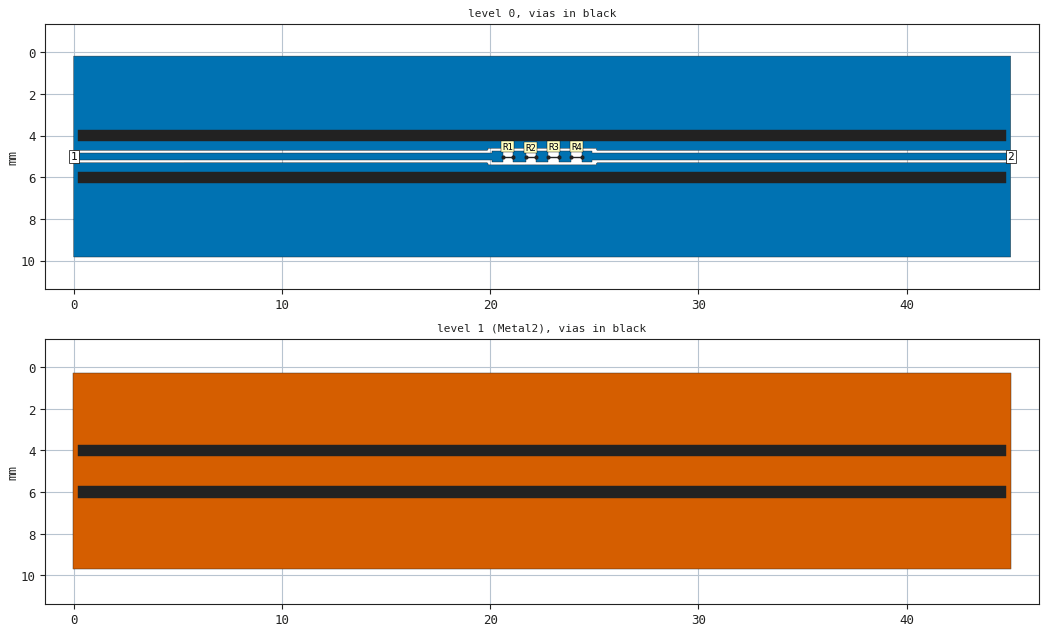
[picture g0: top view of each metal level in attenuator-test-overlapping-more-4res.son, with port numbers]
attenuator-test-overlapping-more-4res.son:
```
FTYP SONPROJ 17 ! Sonnet Project File
VER 17.52.2
HEADER
LIC antikernel2.2.49648 90e2ba8817c0 havequick azonenberg
DAT 08/30/2020 02:43:10
BUILT_BY_CREATED xgeom 16.56 07/03/2018 15:05:41
BUILT_BY_SAVED sonnet 17.52.2
MDATE 08/30/2020 02:41:37
HDATE 08/30/2020 02:41:37
END HEADER
DIM
ANG DEG
CAP PF
CON /OH
FREQ GHZ
IND NH
LNG MM
RES OH
END DIM
CONTROL
VARSWP
OPTIONS  -dj
SPEED 1
CACHE_ABS 1
Q_ACC N
END CONTROL
GEO
TMET "Free Space" 0 FREESPACE 376.7303136 0 0 0
BMET "Free Space" 0 FREESPACE 376.7303136 0 0 0
MET "Silver" 1 TMM 61700000 0.5 0.035 2
BRI "Alumina (96%)" 0 9.4 0.0004 0 
BRI "Alumina (99.5%)" 0 9.9 0.0001 0 
BRI "Aluminum Nitride" 0 8.6 0.0003 0 
BRI "Arlon 25FR" 0 3.58 0.0035 0 
BRI "Arlon 25N" 0 3.38 0.0025 0 
BRI "Arlon AD5" 0 5.1 0.003 0 
BRI "Arlon AD10" 0 10.2 0.005 0 
BRI "Arlon AD250" 0 2.5 0.0018 0 
BRI "Arlon AD255A" 0 2.55 0.0015 0 
BRI "Arlon AD260A" 0 2.6 0.0018 0 
BRI "Arlon AD270" 0 2.7 0.0023 0 
BRI "Arlon AD300A" 0 3 0.002 0 
BRI "Arlon AD320A" 0 3.2 0.0032 0 
BRI "Arlon AD350A" 0 3.5 0.003 0 
BRI "Arlon AD410" 0 4.1 0.003 0 
BRI "Arlon AD430" 0 4.3 0.003 0 
BRI "Arlon AD450" 0 4.5 0.0035 0 
BRI "Arlon AD600" 0 6.15 0.003 0 
BRI "Arlon AD1000" 0 10.2 0.0023 0 
BRI "Arlon AR1000" 0 9.8 0.003 0 
BRI "Arlon CLTE" 0 2.96 0.0023 0 
BRI "Arlon CLTE-AT" 0 3 0.0013 0 
BRI "Arlon CLTE-P" 0 2.94 0.0025 0 
BRI "Arlon CLTE-XT" 0 2.94 0.0012 0 
BRI "Arlon Cu 217LX" 0 2.17 0.0009 0 
BRI "Arlon Cu 233LX" 0 2.33 0.0013 0 
BRI "Arlon Cu 250GT" 0 2.5 0.001 0 
BRI "Arlon Cu 250GX" 0 2.5 0.0018 0 
BRI "Arlon Cu 6250" 0 2.32 0.0013 0 
BRI "Arlon Cu 6700" 0 2.35 0.0025 0 
BRI "Arlon Di 522" 0 2.5 0.001 0 
BRI "Arlon Di 527" 0 2.5 0.0018 0 
BRI "Arlon Di 870" 0 2.33 0.0013 0 
BRI "Arlon Di 880" 0 2.17 0.0009 0 
BRI "Arlon Iso 917" 0 2.17 0.0013 0 
BRI "Arlon Iso 933" 0 2.33 0.0016 0 
BRI "Arlon Multi HF" 0 3.7 0.004 0 
BRI "Arlon TC350" 0 3.5 0.002 0 
BRI "Arlon TC600" 0 6.15 0.002 0 
BRI "Beryllia (99.5%)" 0 6.5 0.0004 0 
BRI "CEM-1" 0 4.5 0.02 0 
BRI "CEM-3" 0 4.5 0.02 0 
BRI "Dupont 9K7" 0 7.1 0.0012 0 
BRI "Dupont 943" 0 7.4 0.002 0 
BRI "Dupont 951" 0 7.8 0.006 0 
BRI "Dupont FEP" 0 2 0.0005 0 
BRI "Dupont Vacrel" 0 3.8 0.011 0 
BRI "ESL 41010" 0 7.5 0.005 0 
BRI "ESL 41020" 0 7.25 0.005 0 
BRI "ESL 41050" 0 13.5 0.002 0 
BRI "ESL 41060" 0 16.5 0.002 0 
BRI "ESL 41110" 0 4.5 0.004 0 
BRI "Ferro A6M" 0 5.9 0.002 0 
BRI "Ferro A6S" 0 5.9 0.002 0 
BRI "Ferro L8" 0 7.3 0.0018 0 
BRI "FR-4" 0 4.4 0.02 0 
BRI "G-10" 0 4.8 0.025 0 
BRI "Gallium Arsenide" 0 12.9 0.006 0 
BRI "Gallium Nitride" 0 9.7 0 0 
BRI "Glass (Pyrex)" 0 4.82 0.0054 0 
BRI "Heraeus HL2000" 0 7.3 0.0026 0 
BRI "Isola 370HR" 0 4.04 0.021 0 
BRI "Isola FR408" 0 3.77 0.0116 0 
BRI "Isola FR408HR" 0 3.68 0.0092 0 
BRI "Isola Getek" 0 3.6 0.01 0 
BRI "Isola GI-180" 0 3.7 0.013 0 
BRI "Isola IS415" 0 3.82 0.0125 0 
BRI "Isola IS620i" 0 3.58 0.006 0 
BRI "Isola IS680-280" 0 2.8 0.0025 0 
BRI "Isola IS680-300" 0 3 0.003 0 
BRI "Isola IS680-320" 0 3.2 0.003 0 
BRI "Isola IS680-333" 0 3.33 0.003 0 
BRI "Isola IS680-338" 0 3.38 0.0032 0 
BRI "Isola IS680-345" 0 3.45 0.0036 0 
BRI "Kerafol CT800" 0 5.3 0.008 0 
BRI "Nelco MW9350" 0 3.7 0.004 0 
BRI "Nelco N4000-12" 0 3.7 0.008 0 
BRI "Nelco N4000-13" 0 3.7 0.009 0 
BRI "Nelco N4000-13SI" 0 3.2 0.007 0 
BRI "Nelco N4000-13EP" 0 3.7 0.008 0 
BRI "Nelco N4350-13RF" 0 3.5 0.0065 0 
BRI "Nelco N4380-13RF" 0 3.8 0.007 0 
BRI "Nelco N9300-13RF" 0 3 0.004 0 
BRI "Nelco N9320-13RF" 0 3.2 0.0045 0 
BRI "Nelco N9338-13RF" 0 3.38 0.0046 0 
BRI "Nelco N9350-13RF" 0 3.48 0.0055 0 
BRI "Nelco NH9294" 0 2.94 0.0022 0 
BRI "Nelco NH9300" 0 3 0.0023 0 
BRI "Nelco NH9320" 0 3.2 0.0024 0 
BRI "Nelco NH9338" 0 3.38 0.0025 0 
BRI "Nelco NH9348" 0 3.48 0.003 0 
BRI "Nelco NH9350" 0 3.5 0.003 0 
BRI "Nelco NH9410" 0 4.1 0.003 0 
BRI "Nelco NH9450" 0 4.5 0.003 0 
BRI "Nelco NX9240" 0 2.4 0.0016 0 
BRI "Nelco NX9245" 0 2.45 0.0016 0 
BRI "Nelco NX9250" 0 2.5 0.0017 0 
BRI "Nelco NX9255" 0 2.55 0.0018 0 
BRI "Nelco NX9260" 0 2.6 0.0019 0 
BRI "Nelco NY9208" 0 2.08 0.0006 0 
BRI "Nelco NY9217" 0 2.17 0.0008 0 
BRI "Nelco NY9220" 0 2.2 0.0009 0 
BRI "Nelco NY9233" 0 2.33 0.0011 0 
BRI "PET" 0 3.37 0.0208 0 
BRI "Polyimide" 0 3.5 0.003 0 
BRI "Quartz (Fused)" 0 3.78 0.0001 0 
BRI "Rogers 3001" 0 2.28 0.003 0 
BRI "Rogers RO2808" 0 7.6 0.0015 0 
BRI "Rogers RO3003" 0 3 0.0013 0 
BRI "Rogers RO3006" 0 6.5 0.002 0 
BRI "Rogers RO3010" 0 11.2 0.0022 0 
BRI "Rogers RO3035" 0 3.6 0.0018 0 
BRI "Rogers RO3203" 0 3.02 0.0016 0 
BRI "Rogers RO3206" 0 6.6 0.0027 0 
BRI "Rogers RO3210" 0 10.8 0.0027 0 
BRI "Rogers RO3730" 0 3 0.0016 0 
BRI "Rogers RO4003C" 0 3.55 0.0029 0 
BRI "Rogers RO4533" 0 3.45 0.0029 0 
BRI "Rogers RO4534" 0 3.4 0.003 0 
BRI "Rogers RO4350B" 0 3.66 0.0037 0 
BRI "Rogers RO4350BTX" 0 3.66 0.0034 0 
BRI "Rogers RO4360" 0 6.15 0.0038 0 
BRI "Rogers RO4450B-3.6" 0 3.3 0.0043 0 
BRI "Rogers RO4450B-4" 0 3.54 0.004 0 
BRI "Rogers RO4450F" 0 3.52 0.0041 0 
BRI "Rogers RO4730" 0 3 0.0033 0 
BRI "Rogers RT5870" 0 2.33 0.0012 0 
BRI "Rogers RT5880" 0 2.2 0.0009 0 
BRI "Rogers RT5880LZ" 0 1.96 0.0019 0 
BRI "Rogers RT6002" 0 2.94 0.0012 0 
BRI "Rogers RT6006" 0 6.15 0.0027 0 
BRI "Rogers RT6010LM" 0 10.9 0.0023 0 
BRI "Rogers RT6035HTC" 0 3.6 0.0013 0 
BRI "Rogers RT6202" 0 2.94 0.0015 0 
BRI "Rogers RT6202PR" 0 2.95 0.0015 0 
BRI "Rogers Syron7000" 0 3.4 0.0045 0 
BRI "Rogers Syron7100-2" 0 3.61 0.006 0 
BRI "Rogers Syron7100-4" 0 3.39 0.005 0 
BRI "Rogers Theta" 0 4.01 0.0118 0 
BRI "Rogers TMM 3" 0 3.39 0.002 0 
BRI "Rogers TMM 4" 0 4.5 0.002 0 
BRI "Rogers TMM 6" 0 6 0.0023 0 
BRI "Rogers TMM 10" 0 9.56 0.0022 0 
BRI "Rogers TMM 10i" 0 9.96 0.002 0 
BRI "Rogers UL2000" 0 2.5 0.0019 0 
BRI "Rogers UL3850" 0 3.05 0.0025 0 
BRI "Rogers UL3908" 0 2.9 0.0025 0 
BRI "Rogers XT8000" 0 3.34 0.0035 0 
BRI "Rogers XT8100-2" 0 3.54 0.0049 0 
BRI "Rogers XT8100-4" 0 3.32 0.0038 0 
BRI "Silicon (intrinsic)" 0 11.9 0.004 0.00044 
BRI "Silicon Dioxide" 0 3.9 0 0 
BRI "Silicon Nitride" 0 7.5 0 0 
BRI "Taconic CER-10" 0 10 0.0035 0 
BRI "Taconic FastFilm" 0 2.7 0.0012 0 
BRI "Taconic Fastrise-DS" 0 2.96 0.0018 0 
BRI "Taconic Fastrise27" 0 2.7 0.0014 0 
BRI "Taconic Fastrise77" 0 7.7 0.0034 0 
BRI "Taconic FEP" 0 2 0.0003 0 
BRI "Taconic RF-30" 0 3 0.0014 0 
BRI "Taconic RF-35" 0 3.5 0.0018 0 
BRI "Taconic RF-35A2" 0 3.5 0.0011 0 
BRI "Taconic RF-35P" 0 3.5 0.0025 0 
BRI "Taconic RF-41" 0 4.1 0.0038 0 
BRI "Taconic RF-43" 0 4.3 0.0033 0 
BRI "Taconic RF-45" 0 4.5 0.0037 0 
BRI "Taconic RF-60A" 0 6.15 0.0038 0 
BRI "Taconic RF-301" 0 2.97 0.0012 0 
BRI "Taconic TacBond HT" 0 2.35 0.0025 0 
BRI "Taconic TLA-6" 0 2.62 0.0012 0 
BRI "Taconic TLC-27" 0 2.75 0.003 0 
BRI "Taconic TLC-30" 0 3 0.003 0 
BRI "Taconic TLC-32" 0 3.2 0.003 0 
BRI "Taconic TLE-95" 0 2.95 0.0028 0 
BRI "Taconic TLF-34" 0 3.4 0.002 0 
BRI "Taconic TLF-35" 0 3.5 0.002 0 
BRI "Taconic TLP-3" 0 2.33 0.0009 0 
BRI "Taconic TLP-5" 0 2.2 0.0009 0 
BRI "Taconic TLP-5A" 0 2.17 0.0009 0 
BRI "Taconic TLT-0" 0 2.45 0.0006 0 
BRI "Taconic TLT-9" 0 2.5 0.0006 0 
BRI "Taconic TLT-8" 0 2.55 0.0006 0 
BRI "Taconic TLT-7" 0 2.6 0.0006 0 
BRI "Taconic TLT-6" 0 2.65 0.0006 0 
BRI "Taconic TLX-0" 0 2.45 0.0019 0 
BRI "Taconic TLX-9" 0 2.5 0.0019 0 
BRI "Taconic TLX-8" 0 2.55 0.0019 0 
BRI "Taconic TLX-7" 0 2.6 0.0019 0 
BRI "Taconic TLX-6" 0 2.65 0.0019 0 
BRI "Taconic TLY-3" 0 2.33 0.0009 0 
BRI "Taconic TLY-3F" 0 2.33 0.0009 0 
BRI "Taconic TLY-5" 0 2.2 0.0009 0 
BRI "Taconic TLY-5-L" 0 2.2 0.0009 0 
BRI "Taconic TLY-5A" 0 2.17 0.0009 0 
BRI "Taconic TLY-5A-L" 0 2.17 0.0009 0 
BRI "Taconic TPG-30" 0 3 0.0038 0 
BRI "Taconic TPG-32" 0 3.2 0.005 0 
BRI "Taconic TPG-35" 0 3.5 0.005 0 
BRI "Taconic TRF-41" 0 4.1 0.0035 0 
BRI "Taconic TRF-43" 0 4.3 0.0035 0 
BRI "Taconic TRF-45" 0 4.5 0.0035 0 
BRI "Taconic TSM-DS" 0 2.85 0.001 0 
BRI "Taconic TSM-DS3" 0 3 0.0011 0 
BRI "Taconic TSM-26" 0 2.6 0.0014 0 
BRI "Taconic TSM-29" 0 2.94 0.0013 0 
BRI "Taconic TSM-30" 0 3 0.0013 0 
BRI "Teflon (PTFE)" 0 2.08 0.0004 0 
BOX 2 45 10 3600 800 20 0
      1 1 1 0 0 0 0 "Air"
      0.16 3.68 1 0.0092 0 0 0 "Isola FR408HR"
      1 1 1 0 0 0 0 "Substrate"
TECHLAY METAL Metal1 <UNSPECIFIED> -2 0 
0 0 0 N 0 1 1 100 100 0 0 0 Y
END
END
TECHLAY VIA Via1 <UNSPECIFIED> -4 0 
VIA POLYGON
1 0 -1 N 0 1 1 100 100 0 0 0 Y
TOLEVEL 0 RING NOCOVERS
END
END
TECHLAY METAL Metal2 <UNSPECIFIED> -3 0 
1 0 -1 N 0 1 1 100 100 0 0 0 Y
END
END
LORGN 0 10 U 
POR1 BOX
POLY 1282 1
3
1 50 0 0 0 0 5 
POR1 BOX
POLY 1285 1
1
2 50 0 0 0 45 5 
SMD 0 "R1"
ID 996
GNDREF AUTO
SBOX 20.725 20.975 4.875 5.125
PBSHW N
LPOS 20.85 4.875
TYPE SPARAM 1
SMDP 0 20.6 5 L 3 1 
EXSMDP
GNDREF AUTO
TERMW FEED
END EXSMDP
SMDP 0 21.1 5 R 4 2 
EXSMDP
GNDREF AUTO
TERMW FEED
END EXSMDP
END
SMD 0 "R2"
ID 999
GNDREF AUTO
SBOX 21.825 22.075 4.9 5.15
PBSHW N
LPOS 21.95 4.9
TYPE SPARAM 2
SMDP 0 21.7 5.025 L 5 1 
EXSMDP
GNDREF AUTO
TERMW FEED
END EXSMDP
SMDP 0 22.2 5.025 R 6 2 
EXSMDP
GNDREF AUTO
TERMW FEED
END EXSMDP
END
SMD 0 "R3"
ID 1002
GNDREF AUTO
SBOX 22.925 23.175 4.875 5.125
PBSHW N
LPOS 23.05 4.875
TYPE SPARAM 2
SMDP 0 22.8 5 L 7 1 
EXSMDP
GNDREF AUTO
TERMW FEED
END EXSMDP
SMDP 0 23.3 5 R 8 2 
EXSMDP
GNDREF AUTO
TERMW FEED
END EXSMDP
END
SMD 0 "R4"
ID 1005
GNDREF AUTO
SBOX 24.025 24.275 4.875 5.125
PBSHW N
LPOS 24.15 4.875
TYPE SPARAM 3
SMDP 0 23.9 5 L 9 1 
EXSMDP
GNDREF AUTO
TERMW FEED
END EXSMDP
SMDP 0 24.4 5 R 10 2 
EXSMDP
GNDREF AUTO
TERMW FEED
END EXSMDP
END
NUM 10
0 5 0 N 1274 1 1 100 100 0 0 0 Y
USER_DAT FromImport
23.9 4.75
23.3 4.75
23.3 5.25
23.9 5.25
23.9 4.75
END
0 5 0 N 1275 1 1 100 100 0 0 0 Y
USER_DAT FromImport
21.7 4.75
21.1 4.75
21.1 5.25
21.7 5.25
21.7 4.75
END
0 5 0 N 1278 1 1 100 100 0 0 0 Y
USER_DAT FromImport
22.8 4.75
22.2 4.75
22.2 5.25
22.8 5.25
22.8 4.75
END
0 9 0 N 1282 1 1 100 100 0 0 0 Y
USER_DAT FromImport
20.6 4.75
20.1 4.75
20.1 4.85
0 4.85
0 5.15
20.1 5.15
20.1 5.25
20.6 5.25
20.6 4.75
END
0 95 0 N 1284 1 1 100 100 0 0 0 Y
USER_DAT FromImport
39.703 4.699
45 4.699
45 0.175
0 0.175
0 4.699
5.297 4.699
5.301 4.6994
5.301 4.6994
5.307 4.7
19.841 4.7
19.847 4.6994
19.853 4.6982
19.859 4.6964
19.864 4.6941
19.87 4.6912
19.875 4.6878
19.88 4.6839
19.884 4.6795
19.888 4.6748
19.891 4.6697
19.894 4.6643
19.896 4.6586
19.898 4.6527
19.899 4.6467
19.9 4.6406
19.9 4.60186
19.90045614 4.600254386
19.903 4.6
20.093 4.6
20.099 4.5994
20.099 4.5994
20.103 4.599
20.597 4.599
20.601 4.5994
20.601 4.5994
20.601 4.5994
20.607 4.6
21.093 4.6
21.099 4.5994
21.099 4.5994
21.103 4.599
21.697 4.599
21.701 4.5994
21.701 4.5994
21.701 4.5994
21.707 4.6
22.193 4.6
22.199 4.5994
22.199 4.5994
22.203 4.599
22.797 4.599
22.801 4.5994
22.801 4.5994
22.801 4.5994
22.807 4.6
23.293 4.6
23.299 4.5994
23.299 4.5994
23.303 4.599
23.897 4.599
23.901 4.5994
23.901 4.5994
23.901 4.5994
23.907 4.6
24.393 4.6
24.399 4.5994
24.399 4.5994
24.403 4.599
24.897 4.599
24.901 4.5994
24.901 4.5994
24.901 4.5994
24.907 4.6
25.097 4.6
25.09954386 4.600254386
25.1 4.60186
25.1 4.6344
25.1 4.6406
25.101 4.6467
25.102 4.6527
25.104 4.6586
25.106 4.6643
25.109 4.6697
25.112 4.6748
25.116 4.6795
25.12 4.6839
25.125 4.6878
25.13 4.6912
25.136 4.6941
25.141 4.6964
25.147 4.6982
25.153 4.6994
25.159 4.7
39.693 4.7
39.703 4.699
END
0 9 0 N 1285 1 1 100 100 0 0 0 Y
USER_DAT FromImport
24.9 5.15
45 5.15
45 4.85
24.9 4.85
24.9 4.75
24.4 4.75
24.4 5.25
24.9 5.25
24.9 5.15
END
0 96 0 N 1286 1 1 100 100 0 0 0 Y
USER_DAT FromImport
45 5.301
39.703 5.301
39.693 5.3
25.159 5.3
25.153 5.3006
25.147 5.3018
25.141 5.3036
25.136 5.3059
25.13 5.3088
25.125 5.3122
25.12 5.3161
25.116 5.3205
25.112 5.3252
25.109 5.3303
25.106 5.3357
25.104 5.3414
25.102 5.3473
25.101 5.3533
25.1 5.3594
25.1 5.3656
25.1 5.39814
25.09954386 5.399745614
25.097 5.4
24.907 5.4
24.901 5.4006
24.901 5.4006
24.901 5.4006
24.897 5.401
24.403 5.401
24.399 5.4006
24.399 5.4006
24.393 5.4
23.907 5.4
23.901 5.4006
23.901 5.4006
23.901 5.4006
23.897 5.401
23.303 5.401
23.299 5.4006
23.299 5.4006
23.293 5.4
22.807 5.4
22.801 5.4006
22.801 5.4006
22.801 5.4006
22.797 5.401
22.203 5.401
22.199 5.4006
22.199 5.4006
22.193 5.4
21.707 5.4
21.701 5.4006
21.701 5.4006
21.701 5.4006
21.697 5.401
21.103 5.401
21.099 5.4006
21.099 5.4006
21.093 5.4
20.607 5.4
20.601 5.4006
20.601 5.4006
20.601 5.4006
20.597 5.401
20.103 5.401
20.099 5.4006
20.099 5.4006
20.093 5.4
19.903 5.4
19.90045614 5.399745614
19.9 5.39814
19.9 5.3656
19.9 5.3594
19.899 5.3533
19.898 5.3473
19.896 5.3414
19.894 5.3357
19.891 5.3303
19.888 5.3252
19.884 5.3205
19.88 5.3161
19.875 5.3122
19.87 5.3088
19.864 5.3059
19.859 5.3036
19.853 5.3018
19.847 5.3006
19.841 5.3
5.307 5.3
5.301 5.3006
5.301 5.3006
5.297 5.301
0 5.301
0 9.825
45 9.825
45 5.301
END
VIA POLYGON
1 5 -1 N 1263 1 1 100 100 0 0 0 Y
TOLEVEL 0 RING NOCOVERS
TLAYNAM Via1 INH
0.2 5.725
44.772 5.725
44.772 6.2747
0.2 6.2747
0.2 5.725
END
VIA POLYGON
1 5 -1 N 1264 1 1 100 100 0 0 0 Y
TOLEVEL 0 RING NOCOVERS
TLAYNAM Via1 INH
0.225 3.725
44.797 3.725
44.797 4.2747
0.225 4.2747
0.225 3.725
END
1 5 -1 N 1266 1 1 100 100 0 0 0 Y
TLAYNAM Metal2 INH
USER_DAT FromImport
-0.013 9.7125
-0.013 0.2875
45 0.2875
45 9.7125
-0.013 9.7125
END
END GEO
OPT
MAX 100
END OPT
VARSWP
ENABLED Y
FREQ Y AY ABS_ENTRY 0.1 6.0 -1 300 
END
END VARSWP
FILEOUT
FOLDER .
END FILEOUT
SMDFILES
1 "../../../../../../share/datasheets/Vishay/0402/FC0402-FlipChip-200 Ohm.s2p"
2 "../../../../../../share/datasheets/Vishay/0402/FC0402-FlipChip-100 Ohm.s2p"
3 "../../../../../../share/datasheets/Vishay/0402/FC0402-FlipChip-50 Ohm.s2p"
END SMDFILES
```
